VERSION 5.7 ;
  NOWIREEXTENSIONATPIN ON ;
  DIVIDERCHAR "/" ;
  BUSBITCHARS "[]" ;
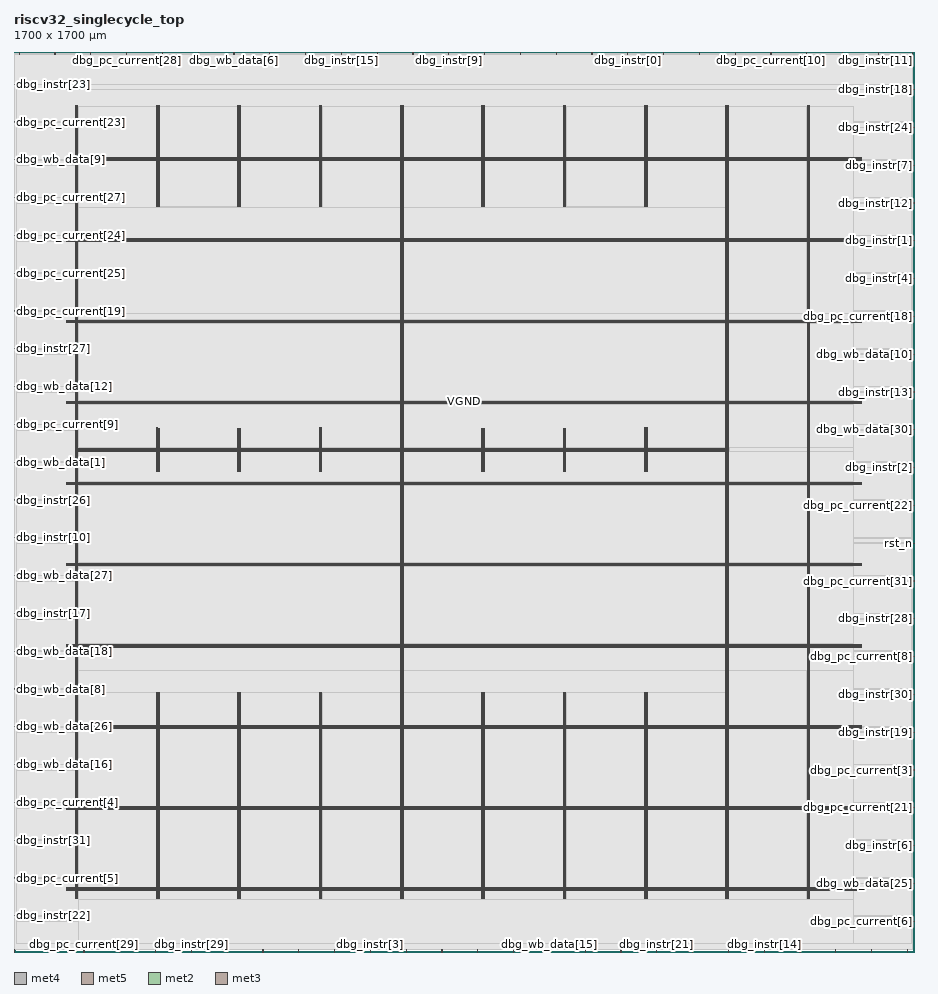
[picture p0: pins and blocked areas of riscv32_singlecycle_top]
MACRO riscv32_singlecycle_top
  CLASS BLOCK ;
  FOREIGN riscv32_singlecycle_top ;
  ORIGIN 0.000 0.000 ;
  SIZE 1700.000 BY 1700.000 ;
  PIN VGND
    DIRECTION INOUT ;
    USE GROUND ;
    PORT
      LAYER met4 ;
        RECT 119.100 100.400 120.700 1599.600 ;
    END
    PORT
      LAYER met4 ;
        RECT 272.700 100.400 274.300 489.400 ;
    END
    PORT
      LAYER met4 ;
        RECT 272.700 907.480 274.300 989.400 ;
    END
    PORT
      LAYER met4 ;
        RECT 272.700 1407.480 274.300 1599.600 ;
    END
    PORT
      LAYER met4 ;
        RECT 426.300 100.400 427.900 489.400 ;
    END
    PORT
      LAYER met4 ;
        RECT 426.300 907.480 427.900 989.400 ;
    END
    PORT
      LAYER met4 ;
        RECT 426.300 1407.480 427.900 1599.600 ;
    END
    PORT
      LAYER met4 ;
        RECT 579.900 100.400 581.500 490.020 ;
    END
    PORT
      LAYER met4 ;
        RECT 579.900 907.480 581.500 990.020 ;
    END
    PORT
      LAYER met4 ;
        RECT 579.900 1407.480 581.500 1599.600 ;
    END
    PORT
      LAYER met4 ;
        RECT 733.500 100.400 735.100 1599.600 ;
    END
    PORT
      LAYER met4 ;
        RECT 887.100 100.400 888.700 489.400 ;
    END
    PORT
      LAYER met4 ;
        RECT 887.100 907.480 888.700 989.400 ;
    END
    PORT
      LAYER met4 ;
        RECT 887.100 1407.480 888.700 1599.600 ;
    END
    PORT
      LAYER met4 ;
        RECT 1040.700 100.400 1042.300 489.400 ;
    END
    PORT
      LAYER met4 ;
        RECT 1040.700 908.100 1042.300 989.400 ;
    END
    PORT
      LAYER met4 ;
        RECT 1040.700 1408.100 1042.300 1599.600 ;
    END
    PORT
      LAYER met4 ;
        RECT 1194.300 100.400 1195.900 490.020 ;
    END
    PORT
      LAYER met4 ;
        RECT 1194.300 907.480 1195.900 990.020 ;
    END
    PORT
      LAYER met4 ;
        RECT 1194.300 1407.480 1195.900 1599.600 ;
    END
    PORT
      LAYER met4 ;
        RECT 1347.900 100.400 1349.500 1599.600 ;
    END
    PORT
      LAYER met4 ;
        RECT 1501.500 100.400 1503.100 1599.600 ;
    END
    PORT
      LAYER met5 ;
        RECT 100.040 119.790 1600.120 121.390 ;
    END
    PORT
      LAYER met5 ;
        RECT 100.040 272.970 1600.120 274.570 ;
    END
    PORT
      LAYER met5 ;
        RECT 100.040 426.150 1600.120 427.750 ;
    END
    PORT
      LAYER met5 ;
        RECT 100.040 579.330 1600.120 580.930 ;
    END
    PORT
      LAYER met5 ;
        RECT 100.040 732.510 1600.120 734.110 ;
    END
    PORT
      LAYER met5 ;
        RECT 100.040 885.690 1600.120 887.290 ;
    END
    PORT
      LAYER met5 ;
        RECT 100.040 1038.870 1600.120 1040.470 ;
    END
    PORT
      LAYER met5 ;
        RECT 100.040 1192.050 1600.120 1193.650 ;
    END
    PORT
      LAYER met5 ;
        RECT 100.040 1345.230 1600.120 1346.830 ;
    END
    PORT
      LAYER met5 ;
        RECT 100.040 1498.410 1600.120 1500.010 ;
    END
    PORT
      LAYER met5 ;
        RECT 115.800 949.500 1349.500 951.100 ;
    END
  END VGND
  PIN VPWR
    DIRECTION INOUT ;
    USE POWER ;
    PORT
      LAYER met4 ;
        RECT 115.800 100.400 117.400 1599.600 ;
    END
    PORT
      LAYER met4 ;
        RECT 269.400 100.400 271.000 490.020 ;
    END
    PORT
      LAYER met4 ;
        RECT 269.400 907.480 271.000 990.020 ;
    END
    PORT
      LAYER met4 ;
        RECT 269.400 1407.480 271.000 1599.600 ;
    END
    PORT
      LAYER met4 ;
        RECT 423.000 100.400 424.600 489.400 ;
    END
    PORT
      LAYER met4 ;
        RECT 423.000 908.100 424.600 989.400 ;
    END
    PORT
      LAYER met4 ;
        RECT 423.000 1408.100 424.600 1599.600 ;
    END
    PORT
      LAYER met4 ;
        RECT 576.600 100.400 578.200 490.020 ;
    END
    PORT
      LAYER met4 ;
        RECT 576.600 907.480 578.200 990.020 ;
    END
    PORT
      LAYER met4 ;
        RECT 576.600 1407.480 578.200 1599.600 ;
    END
    PORT
      LAYER met4 ;
        RECT 730.200 100.400 731.800 1599.600 ;
    END
    PORT
      LAYER met4 ;
        RECT 883.800 100.400 885.400 489.400 ;
    END
    PORT
      LAYER met4 ;
        RECT 883.800 907.480 885.400 989.400 ;
    END
    PORT
      LAYER met4 ;
        RECT 883.800 1407.480 885.400 1599.600 ;
    END
    PORT
      LAYER met4 ;
        RECT 1037.400 100.400 1039.000 489.840 ;
    END
    PORT
      LAYER met4 ;
        RECT 1037.400 907.480 1039.000 989.400 ;
    END
    PORT
      LAYER met4 ;
        RECT 1037.400 1407.480 1039.000 1599.600 ;
    END
    PORT
      LAYER met4 ;
        RECT 1191.000 100.400 1192.600 490.020 ;
    END
    PORT
      LAYER met4 ;
        RECT 1191.000 907.480 1192.600 990.020 ;
    END
    PORT
      LAYER met4 ;
        RECT 1191.000 1407.480 1192.600 1599.600 ;
    END
    PORT
      LAYER met4 ;
        RECT 1344.600 100.400 1346.200 1599.600 ;
    END
    PORT
      LAYER met4 ;
        RECT 1498.200 100.400 1499.800 1599.600 ;
    END
    PORT
      LAYER met5 ;
        RECT 100.040 116.490 1600.120 118.090 ;
    END
    PORT
      LAYER met5 ;
        RECT 100.040 269.670 1600.120 271.270 ;
    END
    PORT
      LAYER met5 ;
        RECT 100.040 422.850 1600.120 424.450 ;
    END
    PORT
      LAYER met5 ;
        RECT 100.040 576.030 1600.120 577.630 ;
    END
    PORT
      LAYER met5 ;
        RECT 100.040 729.210 1600.120 730.810 ;
    END
    PORT
      LAYER met5 ;
        RECT 100.040 882.390 1600.120 883.990 ;
    END
    PORT
      LAYER met5 ;
        RECT 100.040 1035.570 1600.120 1037.170 ;
    END
    PORT
      LAYER met5 ;
        RECT 100.040 1188.750 1600.120 1190.350 ;
    END
    PORT
      LAYER met5 ;
        RECT 100.040 1341.930 1600.120 1343.530 ;
    END
    PORT
      LAYER met5 ;
        RECT 100.040 1495.110 1600.120 1496.710 ;
    END
    PORT
      LAYER met5 ;
        RECT 115.800 946.100 1349.500 947.700 ;
    END
  END VPWR
  PIN clk
    DIRECTION INPUT ;
    USE SIGNAL ;
    ANTENNAGATEAREA 1.721400 ;
    ANTENNADIFFAREA 0.869400 ;
    PORT
      LAYER met2 ;
        RECT 199.730 0.000 200.010 4.000 ;
    END
  END clk
  PIN dbg_instr[0]
    DIRECTION OUTPUT TRISTATE ;
    USE SIGNAL ;
    ANTENNADIFFAREA 0.891000 ;
    PORT
      LAYER met2 ;
        RECT 1159.290 1696.000 1159.570 1700.000 ;
    END
  END dbg_instr[0]
  PIN dbg_instr[10]
    DIRECTION OUTPUT TRISTATE ;
    USE SIGNAL ;
    ANTENNADIFFAREA 0.891000 ;
    PORT
      LAYER met3 ;
        RECT 0.000 782.040 4.000 782.640 ;
    END
  END dbg_instr[10]
  PIN dbg_instr[11]
    DIRECTION OUTPUT TRISTATE ;
    USE SIGNAL ;
    ANTENNADIFFAREA 0.891000 ;
    PORT
      LAYER met2 ;
        RECT 1632.630 1696.000 1632.910 1700.000 ;
    END
  END dbg_instr[11]
  PIN dbg_instr[12]
    DIRECTION OUTPUT TRISTATE ;
    USE SIGNAL ;
    ANTENNADIFFAREA 0.891000 ;
    PORT
      LAYER met3 ;
        RECT 1696.000 1414.440 1700.000 1415.040 ;
    END
  END dbg_instr[12]
  PIN dbg_instr[13]
    DIRECTION OUTPUT TRISTATE ;
    USE SIGNAL ;
    ANTENNADIFFAREA 0.891000 ;
    PORT
      LAYER met3 ;
        RECT 1696.000 1057.440 1700.000 1058.040 ;
    END
  END dbg_instr[13]
  PIN dbg_instr[14]
    DIRECTION OUTPUT TRISTATE ;
    USE SIGNAL ;
    ANTENNADIFFAREA 0.891000 ;
    PORT
      LAYER met2 ;
        RECT 1416.890 0.000 1417.170 4.000 ;
    END
  END dbg_instr[14]
  PIN dbg_instr[15]
    DIRECTION OUTPUT TRISTATE ;
    USE SIGNAL ;
    ANTENNADIFFAREA 0.891000 ;
    PORT
      LAYER met2 ;
        RECT 618.330 1696.000 618.610 1700.000 ;
    END
  END dbg_instr[15]
  PIN dbg_instr[16]
    DIRECTION OUTPUT TRISTATE ;
    USE SIGNAL ;
    ANTENNADIFFAREA 0.891000 ;
    PORT
      LAYER met2 ;
        RECT 685.950 1696.000 686.230 1700.000 ;
    END
  END dbg_instr[16]
  PIN dbg_instr[17]
    DIRECTION OUTPUT TRISTATE ;
    USE SIGNAL ;
    ANTENNADIFFAREA 0.891000 ;
    PORT
      LAYER met3 ;
        RECT 0.000 639.240 4.000 639.840 ;
    END
  END dbg_instr[17]
  PIN dbg_instr[18]
    DIRECTION OUTPUT TRISTATE ;
    USE SIGNAL ;
    ANTENNADIFFAREA 0.891000 ;
    PORT
      LAYER met3 ;
        RECT 1696.000 1628.640 1700.000 1629.240 ;
    END
  END dbg_instr[18]
  PIN dbg_instr[19]
    DIRECTION OUTPUT TRISTATE ;
    USE SIGNAL ;
    ANTENNADIFFAREA 0.891000 ;
    PORT
      LAYER met3 ;
        RECT 1696.000 414.840 1700.000 415.440 ;
    END
  END dbg_instr[19]
  PIN dbg_instr[1]
    DIRECTION OUTPUT TRISTATE ;
    USE SIGNAL ;
    ANTENNADIFFAREA 0.891000 ;
    PORT
      LAYER met3 ;
        RECT 1696.000 1343.040 1700.000 1343.640 ;
    END
  END dbg_instr[1]
  PIN dbg_instr[20]
    DIRECTION OUTPUT TRISTATE ;
    USE SIGNAL ;
    ANTENNADIFFAREA 0.891000 ;
    PORT
      LAYER met2 ;
        RECT 550.710 1696.000 550.990 1700.000 ;
    END
  END dbg_instr[20]
  PIN dbg_instr[21]
    DIRECTION OUTPUT TRISTATE ;
    USE SIGNAL ;
    ANTENNADIFFAREA 0.891000 ;
    PORT
      LAYER met2 ;
        RECT 1214.030 0.000 1214.310 4.000 ;
    END
  END dbg_instr[21]
  PIN dbg_instr[22]
    DIRECTION OUTPUT TRISTATE ;
    USE SIGNAL ;
    ANTENNADIFFAREA 0.891000 ;
    PORT
      LAYER met3 ;
        RECT 0.000 68.040 4.000 68.640 ;
    END
  END dbg_instr[22]
  PIN dbg_instr[23]
    DIRECTION OUTPUT TRISTATE ;
    USE SIGNAL ;
    ANTENNADIFFAREA 0.891000 ;
    PORT
      LAYER met3 ;
        RECT 0.000 1638.840 4.000 1639.440 ;
    END
  END dbg_instr[23]
  PIN dbg_instr[24]
    DIRECTION OUTPUT TRISTATE ;
    USE SIGNAL ;
    ANTENNADIFFAREA 0.891000 ;
    PORT
      LAYER met3 ;
        RECT 1696.000 1557.240 1700.000 1557.840 ;
    END
  END dbg_instr[24]
  PIN dbg_instr[25]
    DIRECTION OUTPUT TRISTATE ;
    USE SIGNAL ;
    ANTENNADIFFAREA 0.891000 ;
    PORT
      LAYER met2 ;
        RECT 483.090 1696.000 483.370 1700.000 ;
    END
  END dbg_instr[25]
  PIN dbg_instr[26]
    DIRECTION OUTPUT TRISTATE ;
    USE SIGNAL ;
    ANTENNADIFFAREA 0.891000 ;
    PORT
      LAYER met3 ;
        RECT 0.000 853.440 4.000 854.040 ;
    END
  END dbg_instr[26]
  PIN dbg_instr[27]
    DIRECTION OUTPUT TRISTATE ;
    USE SIGNAL ;
    ANTENNADIFFAREA 0.891000 ;
    PORT
      LAYER met3 ;
        RECT 0.000 1139.040 4.000 1139.640 ;
    END
  END dbg_instr[27]
  PIN dbg_instr[28]
    DIRECTION OUTPUT TRISTATE ;
    USE SIGNAL ;
    ANTENNADIFFAREA 0.891000 ;
    PORT
      LAYER met3 ;
        RECT 1696.000 629.040 1700.000 629.640 ;
    END
  END dbg_instr[28]
  PIN dbg_instr[29]
    DIRECTION OUTPUT TRISTATE ;
    USE SIGNAL ;
    ANTENNADIFFAREA 0.891000 ;
    PORT
      LAYER met2 ;
        RECT 334.970 0.000 335.250 4.000 ;
    END
  END dbg_instr[29]
  PIN dbg_instr[2]
    DIRECTION OUTPUT TRISTATE ;
    USE SIGNAL ;
    ANTENNADIFFAREA 0.891000 ;
    PORT
      LAYER met3 ;
        RECT 1696.000 914.640 1700.000 915.240 ;
    END
  END dbg_instr[2]
  PIN dbg_instr[30]
    DIRECTION OUTPUT TRISTATE ;
    USE SIGNAL ;
    ANTENNADIFFAREA 0.891000 ;
    PORT
      LAYER met3 ;
        RECT 1696.000 486.240 1700.000 486.840 ;
    END
  END dbg_instr[30]
  PIN dbg_instr[31]
    DIRECTION OUTPUT TRISTATE ;
    USE SIGNAL ;
    ANTENNADIFFAREA 0.891000 ;
    PORT
      LAYER met3 ;
        RECT 0.000 210.840 4.000 211.440 ;
    END
  END dbg_instr[31]
  PIN dbg_instr[3]
    DIRECTION OUTPUT TRISTATE ;
    USE SIGNAL ;
    ANTENNADIFFAREA 0.891000 ;
    PORT
      LAYER met2 ;
        RECT 673.070 0.000 673.350 4.000 ;
    END
  END dbg_instr[3]
  PIN dbg_instr[4]
    DIRECTION OUTPUT TRISTATE ;
    USE SIGNAL ;
    ANTENNADIFFAREA 0.891000 ;
    PORT
      LAYER met3 ;
        RECT 1696.000 1271.640 1700.000 1272.240 ;
    END
  END dbg_instr[4]
  PIN dbg_instr[5]
    DIRECTION OUTPUT TRISTATE ;
    USE SIGNAL ;
    ANTENNADIFFAREA 0.891000 ;
    PORT
      LAYER met2 ;
        RECT 1078.790 0.000 1079.070 4.000 ;
    END
  END dbg_instr[5]
  PIN dbg_instr[6]
    DIRECTION OUTPUT TRISTATE ;
    USE SIGNAL ;
    ANTENNADIFFAREA 0.891000 ;
    PORT
      LAYER met3 ;
        RECT 1696.000 200.640 1700.000 201.240 ;
    END
  END dbg_instr[6]
  PIN dbg_instr[7]
    DIRECTION OUTPUT TRISTATE ;
    USE SIGNAL ;
    ANTENNADIFFAREA 0.891000 ;
    PORT
      LAYER met3 ;
        RECT 1696.000 1485.840 1700.000 1486.440 ;
    END
  END dbg_instr[7]
  PIN dbg_instr[8]
    DIRECTION OUTPUT TRISTATE ;
    USE SIGNAL ;
    ANTENNADIFFAREA 0.891000 ;
    PORT
      LAYER met2 ;
        RECT 1091.670 1696.000 1091.950 1700.000 ;
    END
  END dbg_instr[8]
  PIN dbg_instr[9]
    DIRECTION OUTPUT TRISTATE ;
    USE SIGNAL ;
    ANTENNADIFFAREA 0.891000 ;
    PORT
      LAYER met2 ;
        RECT 821.190 1696.000 821.470 1700.000 ;
    END
  END dbg_instr[9]
  PIN dbg_pc_current[0]
    DIRECTION OUTPUT TRISTATE ;
    USE SIGNAL ;
    ANTENNADIFFAREA 1.590400 ;
    PORT
      LAYER met2 ;
        RECT 9.750 1696.000 10.030 1700.000 ;
    END
  END dbg_pc_current[0]
  PIN dbg_pc_current[10]
    DIRECTION OUTPUT TRISTATE ;
    USE SIGNAL ;
    ANTENNADIFFAREA 0.891000 ;
    PORT
      LAYER met2 ;
        RECT 1429.770 1696.000 1430.050 1700.000 ;
    END
  END dbg_pc_current[10]
  PIN dbg_pc_current[11]
    DIRECTION OUTPUT TRISTATE ;
    USE SIGNAL ;
    ANTENNADIFFAREA 0.891000 ;
    PORT
      LAYER met2 ;
        RECT 402.590 0.000 402.870 4.000 ;
    END
  END dbg_pc_current[11]
  PIN dbg_pc_current[12]
    DIRECTION OUTPUT TRISTATE ;
    USE SIGNAL ;
    ANTENNADIFFAREA 1.590400 ;
    PORT
      LAYER met2 ;
        RECT 1687.370 0.000 1687.650 4.000 ;
    END
  END dbg_pc_current[12]
  PIN dbg_pc_current[13]
    DIRECTION OUTPUT TRISTATE ;
    USE SIGNAL ;
    ANTENNADIFFAREA 0.891000 ;
    PORT
      LAYER met2 ;
        RECT 1552.130 0.000 1552.410 4.000 ;
    END
  END dbg_pc_current[13]
  PIN dbg_pc_current[14]
    DIRECTION OUTPUT TRISTATE ;
    USE SIGNAL ;
    ANTENNADIFFAREA 0.891000 ;
    PORT
      LAYER met2 ;
        RECT 753.570 1696.000 753.850 1700.000 ;
    END
  END dbg_pc_current[14]
  PIN dbg_pc_current[15]
    DIRECTION OUTPUT TRISTATE ;
    USE SIGNAL ;
    ANTENNADIFFAREA 0.891000 ;
    PORT
      LAYER met2 ;
        RECT 956.430 1696.000 956.710 1700.000 ;
    END
  END dbg_pc_current[15]
  PIN dbg_pc_current[16]
    DIRECTION OUTPUT TRISTATE ;
    USE SIGNAL ;
    ANTENNADIFFAREA 0.891000 ;
    PORT
      LAYER met2 ;
        RECT 1497.390 1696.000 1497.670 1700.000 ;
    END
  END dbg_pc_current[16]
  PIN dbg_pc_current[17]
    DIRECTION OUTPUT TRISTATE ;
    USE SIGNAL ;
    ANTENNADIFFAREA 0.891000 ;
    PORT
      LAYER met2 ;
        RECT 1619.750 0.000 1620.030 4.000 ;
    END
  END dbg_pc_current[17]
  PIN dbg_pc_current[18]
    DIRECTION OUTPUT TRISTATE ;
    USE SIGNAL ;
    ANTENNADIFFAREA 0.891000 ;
    PORT
      LAYER met3 ;
        RECT 1696.000 1200.240 1700.000 1200.840 ;
    END
  END dbg_pc_current[18]
  PIN dbg_pc_current[19]
    DIRECTION OUTPUT TRISTATE ;
    USE SIGNAL ;
    ANTENNADIFFAREA 0.891000 ;
    PORT
      LAYER met3 ;
        RECT 0.000 1210.440 4.000 1211.040 ;
    END
  END dbg_pc_current[19]
  PIN dbg_pc_current[1]
    DIRECTION OUTPUT TRISTATE ;
    USE SIGNAL ;
    ANTENNADIFFAREA 0.891000 ;
    PORT
      LAYER met2 ;
        RECT 1024.050 1696.000 1024.330 1700.000 ;
    END
  END dbg_pc_current[1]
  PIN dbg_pc_current[20]
    DIRECTION OUTPUT TRISTATE ;
    USE SIGNAL ;
    ANTENNADIFFAREA 0.891000 ;
    PORT
      LAYER met2 ;
        RECT 605.450 0.000 605.730 4.000 ;
    END
  END dbg_pc_current[20]
  PIN dbg_pc_current[21]
    DIRECTION OUTPUT TRISTATE ;
    USE SIGNAL ;
    ANTENNADIFFAREA 0.891000 ;
    PORT
      LAYER met3 ;
        RECT 1696.000 272.040 1700.000 272.640 ;
    END
  END dbg_pc_current[21]
  PIN dbg_pc_current[22]
    DIRECTION OUTPUT TRISTATE ;
    USE SIGNAL ;
    ANTENNADIFFAREA 0.891000 ;
    PORT
      LAYER met3 ;
        RECT 1696.000 843.240 1700.000 843.840 ;
    END
  END dbg_pc_current[22]
  PIN dbg_pc_current[23]
    DIRECTION OUTPUT TRISTATE ;
    USE SIGNAL ;
    ANTENNADIFFAREA 0.891000 ;
    PORT
      LAYER met3 ;
        RECT 0.000 1567.440 4.000 1568.040 ;
    END
  END dbg_pc_current[23]
  PIN dbg_pc_current[24]
    DIRECTION OUTPUT TRISTATE ;
    USE SIGNAL ;
    ANTENNADIFFAREA 0.891000 ;
    PORT
      LAYER met3 ;
        RECT 0.000 1353.240 4.000 1353.840 ;
    END
  END dbg_pc_current[24]
  PIN dbg_pc_current[25]
    DIRECTION OUTPUT TRISTATE ;
    USE SIGNAL ;
    ANTENNADIFFAREA 0.891000 ;
    PORT
      LAYER met3 ;
        RECT 0.000 1281.840 4.000 1282.440 ;
    END
  END dbg_pc_current[25]
  PIN dbg_pc_current[26]
    DIRECTION OUTPUT TRISTATE ;
    USE SIGNAL ;
    ANTENNADIFFAREA 0.891000 ;
    PORT
      LAYER met2 ;
        RECT 1281.650 0.000 1281.930 4.000 ;
    END
  END dbg_pc_current[26]
  PIN dbg_pc_current[27]
    DIRECTION OUTPUT TRISTATE ;
    USE SIGNAL ;
    ANTENNADIFFAREA 0.891000 ;
    PORT
      LAYER met3 ;
        RECT 0.000 1424.640 4.000 1425.240 ;
    END
  END dbg_pc_current[27]
  PIN dbg_pc_current[28]
    DIRECTION OUTPUT TRISTATE ;
    USE SIGNAL ;
    ANTENNADIFFAREA 0.891000 ;
    PORT
      LAYER met2 ;
        RECT 212.610 1696.000 212.890 1700.000 ;
    END
  END dbg_pc_current[28]
  PIN dbg_pc_current[29]
    DIRECTION OUTPUT TRISTATE ;
    USE SIGNAL ;
    ANTENNADIFFAREA 0.891000 ;
    PORT
      LAYER met2 ;
        RECT 132.110 0.000 132.390 4.000 ;
    END
  END dbg_pc_current[29]
  PIN dbg_pc_current[2]
    DIRECTION OUTPUT TRISTATE ;
    USE SIGNAL ;
    ANTENNADIFFAREA 0.891000 ;
    PORT
      LAYER met2 ;
        RECT 470.210 0.000 470.490 4.000 ;
    END
  END dbg_pc_current[2]
  PIN dbg_pc_current[30]
    DIRECTION OUTPUT TRISTATE ;
    USE SIGNAL ;
    ANTENNADIFFAREA 0.891000 ;
    PORT
      LAYER met2 ;
        RECT 1484.510 0.000 1484.790 4.000 ;
    END
  END dbg_pc_current[30]
  PIN dbg_pc_current[31]
    DIRECTION OUTPUT TRISTATE ;
    USE SIGNAL ;
    ANTENNADIFFAREA 0.891000 ;
    PORT
      LAYER met3 ;
        RECT 1696.000 700.440 1700.000 701.040 ;
    END
  END dbg_pc_current[31]
  PIN dbg_pc_current[3]
    DIRECTION OUTPUT TRISTATE ;
    USE SIGNAL ;
    ANTENNADIFFAREA 0.891000 ;
    PORT
      LAYER met3 ;
        RECT 1696.000 343.440 1700.000 344.040 ;
    END
  END dbg_pc_current[3]
  PIN dbg_pc_current[4]
    DIRECTION OUTPUT TRISTATE ;
    USE SIGNAL ;
    ANTENNADIFFAREA 0.891000 ;
    PORT
      LAYER met3 ;
        RECT 0.000 282.240 4.000 282.840 ;
    END
  END dbg_pc_current[4]
  PIN dbg_pc_current[5]
    DIRECTION OUTPUT TRISTATE ;
    USE SIGNAL ;
    ANTENNADIFFAREA 0.891000 ;
    PORT
      LAYER met3 ;
        RECT 0.000 139.440 4.000 140.040 ;
    END
  END dbg_pc_current[5]
  PIN dbg_pc_current[6]
    DIRECTION OUTPUT TRISTATE ;
    USE SIGNAL ;
    ANTENNADIFFAREA 0.891000 ;
    PORT
      LAYER met3 ;
        RECT 1696.000 57.840 1700.000 58.440 ;
    END
  END dbg_pc_current[6]
  PIN dbg_pc_current[7]
    DIRECTION OUTPUT TRISTATE ;
    USE SIGNAL ;
    ANTENNADIFFAREA 0.891000 ;
    PORT
      LAYER met2 ;
        RECT 280.230 1696.000 280.510 1700.000 ;
    END
  END dbg_pc_current[7]
  PIN dbg_pc_current[8]
    DIRECTION OUTPUT TRISTATE ;
    USE SIGNAL ;
    ANTENNADIFFAREA 0.891000 ;
    PORT
      LAYER met3 ;
        RECT 1696.000 557.640 1700.000 558.240 ;
    END
  END dbg_pc_current[8]
  PIN dbg_pc_current[9]
    DIRECTION OUTPUT TRISTATE ;
    USE SIGNAL ;
    ANTENNADIFFAREA 0.891000 ;
    PORT
      LAYER met3 ;
        RECT 0.000 996.240 4.000 996.840 ;
    END
  END dbg_pc_current[9]
  PIN dbg_wb_data[0]
    DIRECTION OUTPUT TRISTATE ;
    USE SIGNAL ;
    ANTENNADIFFAREA 0.891000 ;
    PORT
      LAYER met2 ;
        RECT 1349.270 0.000 1349.550 4.000 ;
    END
  END dbg_wb_data[0]
  PIN dbg_wb_data[10]
    DIRECTION OUTPUT TRISTATE ;
    USE SIGNAL ;
    ANTENNADIFFAREA 0.891000 ;
    PORT
      LAYER met3 ;
        RECT 1696.000 1128.840 1700.000 1129.440 ;
    END
  END dbg_wb_data[10]
  PIN dbg_wb_data[11]
    DIRECTION OUTPUT TRISTATE ;
    USE SIGNAL ;
    ANTENNADIFFAREA 0.891000 ;
    PORT
      LAYER met2 ;
        RECT 347.850 1696.000 348.130 1700.000 ;
    END
  END dbg_wb_data[11]
  PIN dbg_wb_data[12]
    DIRECTION OUTPUT TRISTATE ;
    USE SIGNAL ;
    ANTENNADIFFAREA 0.891000 ;
    PORT
      LAYER met3 ;
        RECT 0.000 1067.640 4.000 1068.240 ;
    END
  END dbg_wb_data[12]
  PIN dbg_wb_data[13]
    DIRECTION OUTPUT TRISTATE ;
    USE SIGNAL ;
    ANTENNADIFFAREA 0.891000 ;
    PORT
      LAYER met2 ;
        RECT 808.310 0.000 808.590 4.000 ;
    END
  END dbg_wb_data[13]
  PIN dbg_wb_data[14]
    DIRECTION OUTPUT TRISTATE ;
    USE SIGNAL ;
    ANTENNADIFFAREA 1.590400 ;
    PORT
      LAYER met2 ;
        RECT 0.090 0.000 0.370 4.000 ;
    END
  END dbg_wb_data[14]
  PIN dbg_wb_data[15]
    DIRECTION OUTPUT TRISTATE ;
    USE SIGNAL ;
    ANTENNADIFFAREA 0.891000 ;
    PORT
      LAYER met2 ;
        RECT 1011.170 0.000 1011.450 4.000 ;
    END
  END dbg_wb_data[15]
  PIN dbg_wb_data[16]
    DIRECTION OUTPUT TRISTATE ;
    USE SIGNAL ;
    ANTENNADIFFAREA 0.891000 ;
    PORT
      LAYER met3 ;
        RECT 0.000 353.640 4.000 354.240 ;
    END
  END dbg_wb_data[16]
  PIN dbg_wb_data[17]
    DIRECTION OUTPUT TRISTATE ;
    USE SIGNAL ;
    ANTENNADIFFAREA 0.891000 ;
    PORT
      LAYER met2 ;
        RECT 888.810 1696.000 889.090 1700.000 ;
    END
  END dbg_wb_data[17]
  PIN dbg_wb_data[18]
    DIRECTION OUTPUT TRISTATE ;
    USE SIGNAL ;
    ANTENNADIFFAREA 0.891000 ;
    PORT
      LAYER met3 ;
        RECT 0.000 567.840 4.000 568.440 ;
    END
  END dbg_wb_data[18]
  PIN dbg_wb_data[19]
    DIRECTION OUTPUT TRISTATE ;
    USE SIGNAL ;
    ANTENNADIFFAREA 0.891000 ;
    PORT
      LAYER met2 ;
        RECT 77.370 1696.000 77.650 1700.000 ;
    END
  END dbg_wb_data[19]
  PIN dbg_wb_data[1]
    DIRECTION OUTPUT TRISTATE ;
    USE SIGNAL ;
    ANTENNADIFFAREA 0.891000 ;
    PORT
      LAYER met3 ;
        RECT 0.000 924.840 4.000 925.440 ;
    END
  END dbg_wb_data[1]
  PIN dbg_wb_data[20]
    DIRECTION OUTPUT TRISTATE ;
    USE SIGNAL ;
    ANTENNADIFFAREA 0.891000 ;
    PORT
      LAYER met2 ;
        RECT 64.490 0.000 64.770 4.000 ;
    END
  END dbg_wb_data[20]
  PIN dbg_wb_data[21]
    DIRECTION OUTPUT TRISTATE ;
    USE SIGNAL ;
    ANTENNADIFFAREA 0.891000 ;
    PORT
      LAYER met2 ;
        RECT 1565.010 1696.000 1565.290 1700.000 ;
    END
  END dbg_wb_data[21]
  PIN dbg_wb_data[22]
    DIRECTION OUTPUT TRISTATE ;
    USE SIGNAL ;
    ANTENNADIFFAREA 0.891000 ;
    PORT
      LAYER met2 ;
        RECT 1226.910 1696.000 1227.190 1700.000 ;
    END
  END dbg_wb_data[22]
  PIN dbg_wb_data[23]
    DIRECTION OUTPUT TRISTATE ;
    USE SIGNAL ;
    ANTENNADIFFAREA 0.891000 ;
    PORT
      LAYER met2 ;
        RECT 740.690 0.000 740.970 4.000 ;
    END
  END dbg_wb_data[23]
  PIN dbg_wb_data[24]
    DIRECTION OUTPUT TRISTATE ;
    USE SIGNAL ;
    ANTENNADIFFAREA 1.590400 ;
    PORT
      LAYER met2 ;
        RECT 1697.030 1696.000 1697.310 1700.000 ;
    END
  END dbg_wb_data[24]
  PIN dbg_wb_data[25]
    DIRECTION OUTPUT TRISTATE ;
    USE SIGNAL ;
    ANTENNADIFFAREA 0.891000 ;
    PORT
      LAYER met3 ;
        RECT 1696.000 129.240 1700.000 129.840 ;
    END
  END dbg_wb_data[25]
  PIN dbg_wb_data[26]
    DIRECTION OUTPUT TRISTATE ;
    USE SIGNAL ;
    ANTENNADIFFAREA 0.891000 ;
    PORT
      LAYER met3 ;
        RECT 0.000 425.040 4.000 425.640 ;
    END
  END dbg_wb_data[26]
  PIN dbg_wb_data[27]
    DIRECTION OUTPUT TRISTATE ;
    USE SIGNAL ;
    ANTENNADIFFAREA 0.891000 ;
    PORT
      LAYER met3 ;
        RECT 0.000 710.640 4.000 711.240 ;
    END
  END dbg_wb_data[27]
  PIN dbg_wb_data[28]
    DIRECTION OUTPUT TRISTATE ;
    USE SIGNAL ;
    ANTENNADIFFAREA 0.891000 ;
    PORT
      LAYER met2 ;
        RECT 267.350 0.000 267.630 4.000 ;
    END
  END dbg_wb_data[28]
  PIN dbg_wb_data[29]
    DIRECTION OUTPUT TRISTATE ;
    USE SIGNAL ;
    ANTENNADIFFAREA 0.891000 ;
    PORT
      LAYER met2 ;
        RECT 537.830 0.000 538.110 4.000 ;
    END
  END dbg_wb_data[29]
  PIN dbg_wb_data[2]
    DIRECTION OUTPUT TRISTATE ;
    USE SIGNAL ;
    ANTENNADIFFAREA 0.891000 ;
    PORT
      LAYER met2 ;
        RECT 875.930 0.000 876.210 4.000 ;
    END
  END dbg_wb_data[2]
  PIN dbg_wb_data[30]
    DIRECTION OUTPUT TRISTATE ;
    USE SIGNAL ;
    ANTENNADIFFAREA 0.891000 ;
    PORT
      LAYER met3 ;
        RECT 1696.000 986.040 1700.000 986.640 ;
    END
  END dbg_wb_data[30]
  PIN dbg_wb_data[31]
    DIRECTION OUTPUT TRISTATE ;
    USE SIGNAL ;
    ANTENNADIFFAREA 0.891000 ;
    PORT
      LAYER met2 ;
        RECT 943.550 0.000 943.830 4.000 ;
    END
  END dbg_wb_data[31]
  PIN dbg_wb_data[3]
    DIRECTION OUTPUT TRISTATE ;
    USE SIGNAL ;
    ANTENNADIFFAREA 0.891000 ;
    PORT
      LAYER met2 ;
        RECT 1362.150 1696.000 1362.430 1700.000 ;
    END
  END dbg_wb_data[3]
  PIN dbg_wb_data[4]
    DIRECTION OUTPUT TRISTATE ;
    USE SIGNAL ;
    ANTENNADIFFAREA 0.891000 ;
    PORT
      LAYER met2 ;
        RECT 1294.530 1696.000 1294.810 1700.000 ;
    END
  END dbg_wb_data[4]
  PIN dbg_wb_data[5]
    DIRECTION OUTPUT TRISTATE ;
    USE SIGNAL ;
    ANTENNADIFFAREA 0.891000 ;
    PORT
      LAYER met2 ;
        RECT 144.990 1696.000 145.270 1700.000 ;
    END
  END dbg_wb_data[5]
  PIN dbg_wb_data[6]
    DIRECTION OUTPUT TRISTATE ;
    USE SIGNAL ;
    ANTENNADIFFAREA 0.891000 ;
    PORT
      LAYER met2 ;
        RECT 415.470 1696.000 415.750 1700.000 ;
    END
  END dbg_wb_data[6]
  PIN dbg_wb_data[7]
    DIRECTION OUTPUT TRISTATE ;
    USE SIGNAL ;
    ANTENNADIFFAREA 0.891000 ;
    PORT
      LAYER met2 ;
        RECT 1146.410 0.000 1146.690 4.000 ;
    END
  END dbg_wb_data[7]
  PIN dbg_wb_data[8]
    DIRECTION OUTPUT TRISTATE ;
    USE SIGNAL ;
    ANTENNADIFFAREA 0.891000 ;
    PORT
      LAYER met3 ;
        RECT 0.000 496.440 4.000 497.040 ;
    END
  END dbg_wb_data[8]
  PIN dbg_wb_data[9]
    DIRECTION OUTPUT TRISTATE ;
    USE SIGNAL ;
    ANTENNADIFFAREA 0.891000 ;
    PORT
      LAYER met3 ;
        RECT 0.000 1496.040 4.000 1496.640 ;
    END
  END dbg_wb_data[9]
  PIN rst_n
    DIRECTION INPUT ;
    USE SIGNAL ;
    ANTENNAGATEAREA 0.742500 ;
    PORT
      LAYER met3 ;
        RECT 1696.000 771.840 1700.000 772.440 ;
    END
  END rst_n
  OBS
      LAYER li1 ;
        RECT 100.280 100.555 1599.880 1599.445 ;
      LAYER met1 ;
        RECT 0.070 17.040 1697.330 1680.240 ;
      LAYER met2 ;
        RECT 0.100 1695.720 9.470 1696.330 ;
        RECT 10.310 1695.720 77.090 1696.330 ;
        RECT 77.930 1695.720 144.710 1696.330 ;
        RECT 145.550 1695.720 212.330 1696.330 ;
        RECT 213.170 1695.720 279.950 1696.330 ;
        RECT 280.790 1695.720 347.570 1696.330 ;
        RECT 348.410 1695.720 415.190 1696.330 ;
        RECT 416.030 1695.720 482.810 1696.330 ;
        RECT 483.650 1695.720 550.430 1696.330 ;
        RECT 551.270 1695.720 618.050 1696.330 ;
        RECT 618.890 1695.720 685.670 1696.330 ;
        RECT 686.510 1695.720 753.290 1696.330 ;
        RECT 754.130 1695.720 820.910 1696.330 ;
        RECT 821.750 1695.720 888.530 1696.330 ;
        RECT 889.370 1695.720 956.150 1696.330 ;
        RECT 956.990 1695.720 1023.770 1696.330 ;
        RECT 1024.610 1695.720 1091.390 1696.330 ;
        RECT 1092.230 1695.720 1159.010 1696.330 ;
        RECT 1159.850 1695.720 1226.630 1696.330 ;
        RECT 1227.470 1695.720 1294.250 1696.330 ;
        RECT 1295.090 1695.720 1361.870 1696.330 ;
        RECT 1362.710 1695.720 1429.490 1696.330 ;
        RECT 1430.330 1695.720 1497.110 1696.330 ;
        RECT 1497.950 1695.720 1564.730 1696.330 ;
        RECT 1565.570 1695.720 1632.350 1696.330 ;
        RECT 1633.190 1695.720 1696.750 1696.330 ;
        RECT 0.100 4.280 1697.300 1695.720 ;
        RECT 0.650 4.000 64.210 4.280 ;
        RECT 65.050 4.000 131.830 4.280 ;
        RECT 132.670 4.000 199.450 4.280 ;
        RECT 200.290 4.000 267.070 4.280 ;
        RECT 267.910 4.000 334.690 4.280 ;
        RECT 335.530 4.000 402.310 4.280 ;
        RECT 403.150 4.000 469.930 4.280 ;
        RECT 470.770 4.000 537.550 4.280 ;
        RECT 538.390 4.000 605.170 4.280 ;
        RECT 606.010 4.000 672.790 4.280 ;
        RECT 673.630 4.000 740.410 4.280 ;
        RECT 741.250 4.000 808.030 4.280 ;
        RECT 808.870 4.000 875.650 4.280 ;
        RECT 876.490 4.000 943.270 4.280 ;
        RECT 944.110 4.000 1010.890 4.280 ;
        RECT 1011.730 4.000 1078.510 4.280 ;
        RECT 1079.350 4.000 1146.130 4.280 ;
        RECT 1146.970 4.000 1213.750 4.280 ;
        RECT 1214.590 4.000 1281.370 4.280 ;
        RECT 1282.210 4.000 1348.990 4.280 ;
        RECT 1349.830 4.000 1416.610 4.280 ;
        RECT 1417.450 4.000 1484.230 4.280 ;
        RECT 1485.070 4.000 1551.850 4.280 ;
        RECT 1552.690 4.000 1619.470 4.280 ;
        RECT 1620.310 4.000 1687.090 4.280 ;
        RECT 1687.930 4.000 1697.300 4.280 ;
      LAYER met3 ;
        RECT 4.400 1638.440 1696.000 1639.305 ;
        RECT 4.000 1629.640 1696.000 1638.440 ;
        RECT 4.000 1628.240 1695.600 1629.640 ;
        RECT 4.000 1568.440 1696.000 1628.240 ;
        RECT 4.400 1567.040 1696.000 1568.440 ;
        RECT 4.000 1558.240 1696.000 1567.040 ;
        RECT 4.000 1556.840 1695.600 1558.240 ;
        RECT 4.000 1497.040 1696.000 1556.840 ;
        RECT 4.400 1495.640 1696.000 1497.040 ;
        RECT 4.000 1486.840 1696.000 1495.640 ;
        RECT 4.000 1485.440 1695.600 1486.840 ;
        RECT 4.000 1425.640 1696.000 1485.440 ;
        RECT 4.400 1424.240 1696.000 1425.640 ;
        RECT 4.000 1415.440 1696.000 1424.240 ;
        RECT 4.000 1414.040 1695.600 1415.440 ;
        RECT 4.000 1354.240 1696.000 1414.040 ;
        RECT 4.400 1352.840 1696.000 1354.240 ;
        RECT 4.000 1344.040 1696.000 1352.840 ;
        RECT 4.000 1342.640 1695.600 1344.040 ;
        RECT 4.000 1282.840 1696.000 1342.640 ;
        RECT 4.400 1281.440 1696.000 1282.840 ;
        RECT 4.000 1272.640 1696.000 1281.440 ;
        RECT 4.000 1271.240 1695.600 1272.640 ;
        RECT 4.000 1211.440 1696.000 1271.240 ;
        RECT 4.400 1210.040 1696.000 1211.440 ;
        RECT 4.000 1201.240 1696.000 1210.040 ;
        RECT 4.000 1199.840 1695.600 1201.240 ;
        RECT 4.000 1140.040 1696.000 1199.840 ;
        RECT 4.400 1138.640 1696.000 1140.040 ;
        RECT 4.000 1129.840 1696.000 1138.640 ;
        RECT 4.000 1128.440 1695.600 1129.840 ;
        RECT 4.000 1068.640 1696.000 1128.440 ;
        RECT 4.400 1067.240 1696.000 1068.640 ;
        RECT 4.000 1058.440 1696.000 1067.240 ;
        RECT 4.000 1057.040 1695.600 1058.440 ;
        RECT 4.000 997.240 1696.000 1057.040 ;
        RECT 4.400 995.840 1696.000 997.240 ;
        RECT 4.000 987.040 1696.000 995.840 ;
        RECT 4.000 985.640 1695.600 987.040 ;
        RECT 4.000 925.840 1696.000 985.640 ;
        RECT 4.400 924.440 1696.000 925.840 ;
        RECT 4.000 915.640 1696.000 924.440 ;
        RECT 4.000 914.240 1695.600 915.640 ;
        RECT 4.000 854.440 1696.000 914.240 ;
        RECT 4.400 853.040 1696.000 854.440 ;
        RECT 4.000 844.240 1696.000 853.040 ;
        RECT 4.000 842.840 1695.600 844.240 ;
        RECT 4.000 783.040 1696.000 842.840 ;
        RECT 4.400 781.640 1696.000 783.040 ;
        RECT 4.000 772.840 1696.000 781.640 ;
        RECT 4.000 771.440 1695.600 772.840 ;
        RECT 4.000 711.640 1696.000 771.440 ;
        RECT 4.400 710.240 1696.000 711.640 ;
        RECT 4.000 701.440 1696.000 710.240 ;
        RECT 4.000 700.040 1695.600 701.440 ;
        RECT 4.000 640.240 1696.000 700.040 ;
        RECT 4.400 638.840 1696.000 640.240 ;
        RECT 4.000 630.040 1696.000 638.840 ;
        RECT 4.000 628.640 1695.600 630.040 ;
        RECT 4.000 568.840 1696.000 628.640 ;
        RECT 4.400 567.440 1696.000 568.840 ;
        RECT 4.000 558.640 1696.000 567.440 ;
        RECT 4.000 557.240 1695.600 558.640 ;
        RECT 4.000 497.440 1696.000 557.240 ;
        RECT 4.400 496.040 1696.000 497.440 ;
        RECT 4.000 487.240 1696.000 496.040 ;
        RECT 4.000 485.840 1695.600 487.240 ;
        RECT 4.000 426.040 1696.000 485.840 ;
        RECT 4.400 424.640 1696.000 426.040 ;
        RECT 4.000 415.840 1696.000 424.640 ;
        RECT 4.000 414.440 1695.600 415.840 ;
        RECT 4.000 354.640 1696.000 414.440 ;
        RECT 4.400 353.240 1696.000 354.640 ;
        RECT 4.000 344.440 1696.000 353.240 ;
        RECT 4.000 343.040 1695.600 344.440 ;
        RECT 4.000 283.240 1696.000 343.040 ;
        RECT 4.400 281.840 1696.000 283.240 ;
        RECT 4.000 273.040 1696.000 281.840 ;
        RECT 4.000 271.640 1695.600 273.040 ;
        RECT 4.000 211.840 1696.000 271.640 ;
        RECT 4.400 210.440 1696.000 211.840 ;
        RECT 4.000 201.640 1696.000 210.440 ;
        RECT 4.000 200.240 1695.600 201.640 ;
        RECT 4.000 140.440 1696.000 200.240 ;
        RECT 4.400 139.040 1696.000 140.440 ;
        RECT 4.000 130.240 1696.000 139.040 ;
        RECT 4.000 128.840 1695.600 130.240 ;
        RECT 4.000 69.040 1696.000 128.840 ;
        RECT 4.400 67.640 1696.000 69.040 ;
        RECT 4.000 58.840 1696.000 67.640 ;
        RECT 4.000 57.440 1695.600 58.840 ;
        RECT 4.000 16.495 1696.000 57.440 ;
      LAYER met4 ;
        RECT 121.310 1407.080 269.000 1597.825 ;
        RECT 271.400 1407.080 272.300 1597.825 ;
        RECT 274.700 1407.700 422.600 1597.825 ;
        RECT 425.000 1407.700 425.900 1597.825 ;
        RECT 274.700 1407.080 425.900 1407.700 ;
        RECT 428.300 1407.080 576.200 1597.825 ;
        RECT 578.600 1407.080 579.500 1597.825 ;
        RECT 581.900 1407.080 729.800 1597.825 ;
        RECT 121.310 990.420 729.800 1407.080 ;
        RECT 121.310 907.080 269.000 990.420 ;
        RECT 271.400 989.800 576.200 990.420 ;
        RECT 271.400 907.080 272.300 989.800 ;
        RECT 274.700 907.700 422.600 989.800 ;
        RECT 425.000 907.700 425.900 989.800 ;
        RECT 274.700 907.080 425.900 907.700 ;
        RECT 428.300 907.080 576.200 989.800 ;
        RECT 578.600 907.080 579.500 990.420 ;
        RECT 581.900 907.080 729.800 990.420 ;
        RECT 121.310 490.420 729.800 907.080 ;
        RECT 121.310 100.000 269.000 490.420 ;
        RECT 271.400 489.800 576.200 490.420 ;
        RECT 271.400 100.000 272.300 489.800 ;
        RECT 274.700 100.000 422.600 489.800 ;
        RECT 425.000 100.000 425.900 489.800 ;
        RECT 428.300 100.000 576.200 489.800 ;
        RECT 578.600 100.000 579.500 490.420 ;
        RECT 581.900 100.000 729.800 490.420 ;
        RECT 732.200 100.000 733.100 1597.825 ;
        RECT 735.500 1407.080 883.400 1597.825 ;
        RECT 885.800 1407.080 886.700 1597.825 ;
        RECT 889.100 1407.080 1037.000 1597.825 ;
        RECT 1039.400 1407.700 1040.300 1597.825 ;
        RECT 1042.700 1407.700 1190.600 1597.825 ;
        RECT 1039.400 1407.080 1190.600 1407.700 ;
        RECT 1193.000 1407.080 1193.900 1597.825 ;
        RECT 1196.300 1407.080 1344.200 1597.825 ;
        RECT 735.500 990.420 1344.200 1407.080 ;
        RECT 735.500 989.800 1190.600 990.420 ;
        RECT 735.500 907.080 883.400 989.800 ;
        RECT 885.800 907.080 886.700 989.800 ;
        RECT 889.100 907.080 1037.000 989.800 ;
        RECT 1039.400 907.700 1040.300 989.800 ;
        RECT 1042.700 907.700 1190.600 989.800 ;
        RECT 1039.400 907.080 1190.600 907.700 ;
        RECT 1193.000 907.080 1193.900 990.420 ;
        RECT 1196.300 907.080 1344.200 990.420 ;
        RECT 735.500 490.420 1344.200 907.080 ;
        RECT 735.500 490.240 1190.600 490.420 ;
        RECT 735.500 489.800 1037.000 490.240 ;
        RECT 735.500 100.000 883.400 489.800 ;
        RECT 885.800 100.000 886.700 489.800 ;
        RECT 889.100 100.000 1037.000 489.800 ;
        RECT 1039.400 489.800 1190.600 490.240 ;
        RECT 1039.400 100.000 1040.300 489.800 ;
        RECT 1042.700 100.000 1190.600 489.800 ;
        RECT 1193.000 100.000 1193.900 490.420 ;
        RECT 1196.300 100.000 1344.200 490.420 ;
        RECT 1346.600 100.000 1347.500 1597.825 ;
        RECT 1349.900 100.000 1497.800 1597.825 ;
        RECT 1500.200 100.000 1501.100 1597.825 ;
        RECT 1503.500 100.000 1586.210 1597.825 ;
        RECT 121.310 16.495 1586.210 100.000 ;
      LAYER met5 ;
        RECT 121.100 1195.250 1586.420 1206.100 ;
        RECT 121.100 1042.070 1586.420 1187.150 ;
        RECT 121.100 952.700 1586.420 1033.970 ;
        RECT 1351.100 944.500 1586.420 952.700 ;
        RECT 121.100 888.890 1586.420 944.500 ;
        RECT 121.100 735.710 1586.420 880.790 ;
        RECT 121.100 582.530 1586.420 727.610 ;
        RECT 121.100 531.300 1586.420 574.430 ;
  END
END riscv32_singlecycle_top
END LIBRARY

